VERSION 5.7 ;
BUSBITCHARS "[]" ;
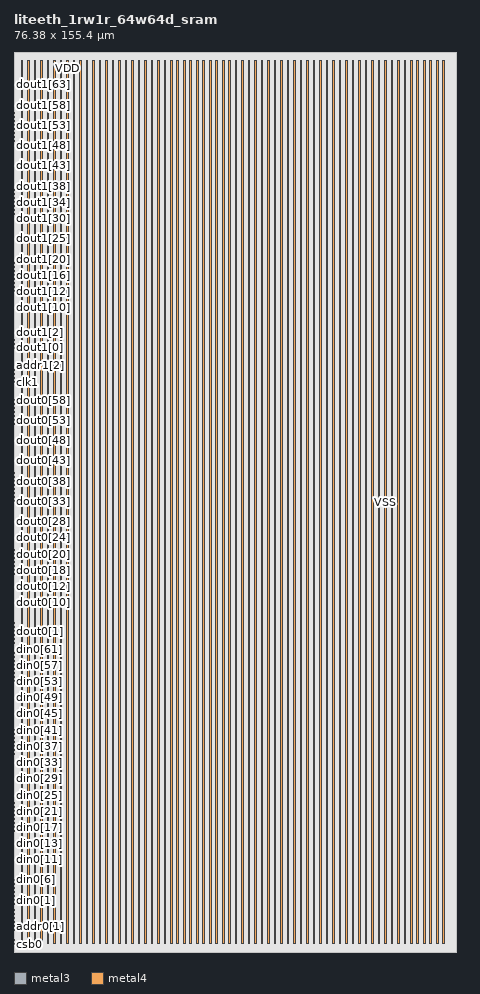
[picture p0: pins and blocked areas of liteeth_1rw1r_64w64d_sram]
MACRO liteeth_1rw1r_64w64d_sram
  FOREIGN liteeth_1rw1r_64w64d_sram 0 0 ;
  SYMMETRY X Y R90 ;
  SIZE 76.380 BY 155.400 ;
  CLASS BLOCK ;
  PIN clk0
    DIRECTION INPUT ;
    USE SIGNAL ;
    SHAPE ABUTMENT ;
    PORT
      LAYER metal3 ;
      RECT 0.000 1.365 0.070 1.435 ;
    END
  END clk0
  PIN csb0
    DIRECTION INPUT ;
    USE SIGNAL ;
    SHAPE ABUTMENT ;
    PORT
      LAYER metal3 ;
      RECT 0.000 2.065 0.070 2.135 ;
    END
  END csb0
  PIN web0
    DIRECTION INPUT ;
    USE SIGNAL ;
    SHAPE ABUTMENT ;
    PORT
      LAYER metal3 ;
      RECT 0.000 2.765 0.070 2.835 ;
    END
  END web0
  PIN addr0[0]
    DIRECTION INPUT ;
    USE SIGNAL ;
    SHAPE ABUTMENT ;
    PORT
      LAYER metal3 ;
      RECT 0.000 3.745 0.070 3.815 ;
    END
  END addr0[0]
  PIN addr0[1]
    DIRECTION INPUT ;
    USE SIGNAL ;
    SHAPE ABUTMENT ;
    PORT
      LAYER metal3 ;
      RECT 0.000 4.445 0.070 4.515 ;
    END
  END addr0[1]
  PIN addr0[2]
    DIRECTION INPUT ;
    USE SIGNAL ;
    SHAPE ABUTMENT ;
    PORT
      LAYER metal3 ;
      RECT 0.000 5.145 0.070 5.215 ;
    END
  END addr0[2]
  PIN addr0[3]
    DIRECTION INPUT ;
    USE SIGNAL ;
    SHAPE ABUTMENT ;
    PORT
      LAYER metal3 ;
      RECT 0.000 5.845 0.070 5.915 ;
    END
  END addr0[3]
  PIN addr0[4]
    DIRECTION INPUT ;
    USE SIGNAL ;
    SHAPE ABUTMENT ;
    PORT
      LAYER metal3 ;
      RECT 0.000 6.545 0.070 6.615 ;
    END
  END addr0[4]
  PIN addr0[5]
    DIRECTION INPUT ;
    USE SIGNAL ;
    SHAPE ABUTMENT ;
    PORT
      LAYER metal3 ;
      RECT 0.000 7.245 0.070 7.315 ;
    END
  END addr0[5]
  PIN din0[0]
    DIRECTION INPUT ;
    USE SIGNAL ;
    SHAPE ABUTMENT ;
    PORT
      LAYER metal3 ;
      RECT 0.000 8.225 0.070 8.295 ;
    END
  END din0[0]
  PIN din0[1]
    DIRECTION INPUT ;
    USE SIGNAL ;
    SHAPE ABUTMENT ;
    PORT
      LAYER metal3 ;
      RECT 0.000 8.925 0.070 8.995 ;
    END
  END din0[1]
  PIN din0[2]
    DIRECTION INPUT ;
    USE SIGNAL ;
    SHAPE ABUTMENT ;
    PORT
      LAYER metal3 ;
      RECT 0.000 9.625 0.070 9.695 ;
    END
  END din0[2]
  PIN din0[3]
    DIRECTION INPUT ;
    USE SIGNAL ;
    SHAPE ABUTMENT ;
    PORT
      LAYER metal3 ;
      RECT 0.000 10.325 0.070 10.395 ;
    END
  END din0[3]
  PIN din0[4]
    DIRECTION INPUT ;
    USE SIGNAL ;
    SHAPE ABUTMENT ;
    PORT
      LAYER metal3 ;
      RECT 0.000 11.025 0.070 11.095 ;
    END
  END din0[4]
  PIN din0[5]
    DIRECTION INPUT ;
    USE SIGNAL ;
    SHAPE ABUTMENT ;
    PORT
      LAYER metal3 ;
      RECT 0.000 11.725 0.070 11.795 ;
    END
  END din0[5]
  PIN din0[6]
    DIRECTION INPUT ;
    USE SIGNAL ;
    SHAPE ABUTMENT ;
    PORT
      LAYER metal3 ;
      RECT 0.000 12.425 0.070 12.495 ;
    END
  END din0[6]
  PIN din0[7]
    DIRECTION INPUT ;
    USE SIGNAL ;
    SHAPE ABUTMENT ;
    PORT
      LAYER metal3 ;
      RECT 0.000 13.125 0.070 13.195 ;
    END
  END din0[7]
  PIN din0[8]
    DIRECTION INPUT ;
    USE SIGNAL ;
    SHAPE ABUTMENT ;
    PORT
      LAYER metal3 ;
      RECT 0.000 13.825 0.070 13.895 ;
    END
  END din0[8]
  PIN din0[9]
    DIRECTION INPUT ;
    USE SIGNAL ;
    SHAPE ABUTMENT ;
    PORT
      LAYER metal3 ;
      RECT 0.000 14.525 0.070 14.595 ;
    END
  END din0[9]
  PIN din0[10]
    DIRECTION INPUT ;
    USE SIGNAL ;
    SHAPE ABUTMENT ;
    PORT
      LAYER metal3 ;
      RECT 0.000 15.225 0.070 15.295 ;
    END
  END din0[10]
  PIN din0[11]
    DIRECTION INPUT ;
    USE SIGNAL ;
    SHAPE ABUTMENT ;
    PORT
      LAYER metal3 ;
      RECT 0.000 15.925 0.070 15.995 ;
    END
  END din0[11]
  PIN din0[12]
    DIRECTION INPUT ;
    USE SIGNAL ;
    SHAPE ABUTMENT ;
    PORT
      LAYER metal3 ;
      RECT 0.000 16.625 0.070 16.695 ;
    END
  END din0[12]
  PIN din0[13]
    DIRECTION INPUT ;
    USE SIGNAL ;
    SHAPE ABUTMENT ;
    PORT
      LAYER metal3 ;
      RECT 0.000 17.325 0.070 17.395 ;
    END
  END din0[13]
  PIN din0[14]
    DIRECTION INPUT ;
    USE SIGNAL ;
    SHAPE ABUTMENT ;
    PORT
      LAYER metal3 ;
      RECT 0.000 18.025 0.070 18.095 ;
    END
  END din0[14]
  PIN din0[15]
    DIRECTION INPUT ;
    USE SIGNAL ;
    SHAPE ABUTMENT ;
    PORT
      LAYER metal3 ;
      RECT 0.000 18.725 0.070 18.795 ;
    END
  END din0[15]
  PIN din0[16]
    DIRECTION INPUT ;
    USE SIGNAL ;
    SHAPE ABUTMENT ;
    PORT
      LAYER metal3 ;
      RECT 0.000 19.425 0.070 19.495 ;
    END
  END din0[16]
  PIN din0[17]
    DIRECTION INPUT ;
    USE SIGNAL ;
    SHAPE ABUTMENT ;
    PORT
      LAYER metal3 ;
      RECT 0.000 20.125 0.070 20.195 ;
    END
  END din0[17]
  PIN din0[18]
    DIRECTION INPUT ;
    USE SIGNAL ;
    SHAPE ABUTMENT ;
    PORT
      LAYER metal3 ;
      RECT 0.000 20.825 0.070 20.895 ;
    END
  END din0[18]
  PIN din0[19]
    DIRECTION INPUT ;
    USE SIGNAL ;
    SHAPE ABUTMENT ;
    PORT
      LAYER metal3 ;
      RECT 0.000 21.525 0.070 21.595 ;
    END
  END din0[19]
  PIN din0[20]
    DIRECTION INPUT ;
    USE SIGNAL ;
    SHAPE ABUTMENT ;
    PORT
      LAYER metal3 ;
      RECT 0.000 22.225 0.070 22.295 ;
    END
  END din0[20]
  PIN din0[21]
    DIRECTION INPUT ;
    USE SIGNAL ;
    SHAPE ABUTMENT ;
    PORT
      LAYER metal3 ;
      RECT 0.000 22.925 0.070 22.995 ;
    END
  END din0[21]
  PIN din0[22]
    DIRECTION INPUT ;
    USE SIGNAL ;
    SHAPE ABUTMENT ;
    PORT
      LAYER metal3 ;
      RECT 0.000 23.625 0.070 23.695 ;
    END
  END din0[22]
  PIN din0[23]
    DIRECTION INPUT ;
    USE SIGNAL ;
    SHAPE ABUTMENT ;
    PORT
      LAYER metal3 ;
      RECT 0.000 24.325 0.070 24.395 ;
    END
  END din0[23]
  PIN din0[24]
    DIRECTION INPUT ;
    USE SIGNAL ;
    SHAPE ABUTMENT ;
    PORT
      LAYER metal3 ;
      RECT 0.000 25.025 0.070 25.095 ;
    END
  END din0[24]
  PIN din0[25]
    DIRECTION INPUT ;
    USE SIGNAL ;
    SHAPE ABUTMENT ;
    PORT
      LAYER metal3 ;
      RECT 0.000 25.725 0.070 25.795 ;
    END
  END din0[25]
  PIN din0[26]
    DIRECTION INPUT ;
    USE SIGNAL ;
    SHAPE ABUTMENT ;
    PORT
      LAYER metal3 ;
      RECT 0.000 26.425 0.070 26.495 ;
    END
  END din0[26]
  PIN din0[27]
    DIRECTION INPUT ;
    USE SIGNAL ;
    SHAPE ABUTMENT ;
    PORT
      LAYER metal3 ;
      RECT 0.000 27.125 0.070 27.195 ;
    END
  END din0[27]
  PIN din0[28]
    DIRECTION INPUT ;
    USE SIGNAL ;
    SHAPE ABUTMENT ;
    PORT
      LAYER metal3 ;
      RECT 0.000 27.825 0.070 27.895 ;
    END
  END din0[28]
  PIN din0[29]
    DIRECTION INPUT ;
    USE SIGNAL ;
    SHAPE ABUTMENT ;
    PORT
      LAYER metal3 ;
      RECT 0.000 28.525 0.070 28.595 ;
    END
  END din0[29]
  PIN din0[30]
    DIRECTION INPUT ;
    USE SIGNAL ;
    SHAPE ABUTMENT ;
    PORT
      LAYER metal3 ;
      RECT 0.000 29.225 0.070 29.295 ;
    END
  END din0[30]
  PIN din0[31]
    DIRECTION INPUT ;
    USE SIGNAL ;
    SHAPE ABUTMENT ;
    PORT
      LAYER metal3 ;
      RECT 0.000 29.925 0.070 29.995 ;
    END
  END din0[31]
  PIN din0[32]
    DIRECTION INPUT ;
    USE SIGNAL ;
    SHAPE ABUTMENT ;
    PORT
      LAYER metal3 ;
      RECT 0.000 30.625 0.070 30.695 ;
    END
  END din0[32]
  PIN din0[33]
    DIRECTION INPUT ;
    USE SIGNAL ;
    SHAPE ABUTMENT ;
    PORT
      LAYER metal3 ;
      RECT 0.000 31.325 0.070 31.395 ;
    END
  END din0[33]
  PIN din0[34]
    DIRECTION INPUT ;
    USE SIGNAL ;
    SHAPE ABUTMENT ;
    PORT
      LAYER metal3 ;
      RECT 0.000 32.025 0.070 32.095 ;
    END
  END din0[34]
  PIN din0[35]
    DIRECTION INPUT ;
    USE SIGNAL ;
    SHAPE ABUTMENT ;
    PORT
      LAYER metal3 ;
      RECT 0.000 32.725 0.070 32.795 ;
    END
  END din0[35]
  PIN din0[36]
    DIRECTION INPUT ;
    USE SIGNAL ;
    SHAPE ABUTMENT ;
    PORT
      LAYER metal3 ;
      RECT 0.000 33.425 0.070 33.495 ;
    END
  END din0[36]
  PIN din0[37]
    DIRECTION INPUT ;
    USE SIGNAL ;
    SHAPE ABUTMENT ;
    PORT
      LAYER metal3 ;
      RECT 0.000 34.125 0.070 34.195 ;
    END
  END din0[37]
  PIN din0[38]
    DIRECTION INPUT ;
    USE SIGNAL ;
    SHAPE ABUTMENT ;
    PORT
      LAYER metal3 ;
      RECT 0.000 34.825 0.070 34.895 ;
    END
  END din0[38]
  PIN din0[39]
    DIRECTION INPUT ;
    USE SIGNAL ;
    SHAPE ABUTMENT ;
    PORT
      LAYER metal3 ;
      RECT 0.000 35.525 0.070 35.595 ;
    END
  END din0[39]
  PIN din0[40]
    DIRECTION INPUT ;
    USE SIGNAL ;
    SHAPE ABUTMENT ;
    PORT
      LAYER metal3 ;
      RECT 0.000 36.225 0.070 36.295 ;
    END
  END din0[40]
  PIN din0[41]
    DIRECTION INPUT ;
    USE SIGNAL ;
    SHAPE ABUTMENT ;
    PORT
      LAYER metal3 ;
      RECT 0.000 36.925 0.070 36.995 ;
    END
  END din0[41]
  PIN din0[42]
    DIRECTION INPUT ;
    USE SIGNAL ;
    SHAPE ABUTMENT ;
    PORT
      LAYER metal3 ;
      RECT 0.000 37.625 0.070 37.695 ;
    END
  END din0[42]
  PIN din0[43]
    DIRECTION INPUT ;
    USE SIGNAL ;
    SHAPE ABUTMENT ;
    PORT
      LAYER metal3 ;
      RECT 0.000 38.325 0.070 38.395 ;
    END
  END din0[43]
  PIN din0[44]
    DIRECTION INPUT ;
    USE SIGNAL ;
    SHAPE ABUTMENT ;
    PORT
      LAYER metal3 ;
      RECT 0.000 39.025 0.070 39.095 ;
    END
  END din0[44]
  PIN din0[45]
    DIRECTION INPUT ;
    USE SIGNAL ;
    SHAPE ABUTMENT ;
    PORT
      LAYER metal3 ;
      RECT 0.000 39.725 0.070 39.795 ;
    END
  END din0[45]
  PIN din0[46]
    DIRECTION INPUT ;
    USE SIGNAL ;
    SHAPE ABUTMENT ;
    PORT
      LAYER metal3 ;
      RECT 0.000 40.425 0.070 40.495 ;
    END
  END din0[46]
  PIN din0[47]
    DIRECTION INPUT ;
    USE SIGNAL ;
    SHAPE ABUTMENT ;
    PORT
      LAYER metal3 ;
      RECT 0.000 41.125 0.070 41.195 ;
    END
  END din0[47]
  PIN din0[48]
    DIRECTION INPUT ;
    USE SIGNAL ;
    SHAPE ABUTMENT ;
    PORT
      LAYER metal3 ;
      RECT 0.000 41.825 0.070 41.895 ;
    END
  END din0[48]
  PIN din0[49]
    DIRECTION INPUT ;
    USE SIGNAL ;
    SHAPE ABUTMENT ;
    PORT
      LAYER metal3 ;
      RECT 0.000 42.525 0.070 42.595 ;
    END
  END din0[49]
  PIN din0[50]
    DIRECTION INPUT ;
    USE SIGNAL ;
    SHAPE ABUTMENT ;
    PORT
      LAYER metal3 ;
      RECT 0.000 43.225 0.070 43.295 ;
    END
  END din0[50]
  PIN din0[51]
    DIRECTION INPUT ;
    USE SIGNAL ;
    SHAPE ABUTMENT ;
    PORT
      LAYER metal3 ;
      RECT 0.000 43.925 0.070 43.995 ;
    END
  END din0[51]
  PIN din0[52]
    DIRECTION INPUT ;
    USE SIGNAL ;
    SHAPE ABUTMENT ;
    PORT
      LAYER metal3 ;
      RECT 0.000 44.625 0.070 44.695 ;
    END
  END din0[52]
  PIN din0[53]
    DIRECTION INPUT ;
    USE SIGNAL ;
    SHAPE ABUTMENT ;
    PORT
      LAYER metal3 ;
      RECT 0.000 45.325 0.070 45.395 ;
    END
  END din0[53]
  PIN din0[54]
    DIRECTION INPUT ;
    USE SIGNAL ;
    SHAPE ABUTMENT ;
    PORT
      LAYER metal3 ;
      RECT 0.000 46.025 0.070 46.095 ;
    END
  END din0[54]
  PIN din0[55]
    DIRECTION INPUT ;
    USE SIGNAL ;
    SHAPE ABUTMENT ;
    PORT
      LAYER metal3 ;
      RECT 0.000 46.725 0.070 46.795 ;
    END
  END din0[55]
  PIN din0[56]
    DIRECTION INPUT ;
    USE SIGNAL ;
    SHAPE ABUTMENT ;
    PORT
      LAYER metal3 ;
      RECT 0.000 47.425 0.070 47.495 ;
    END
  END din0[56]
  PIN din0[57]
    DIRECTION INPUT ;
    USE SIGNAL ;
    SHAPE ABUTMENT ;
    PORT
      LAYER metal3 ;
      RECT 0.000 48.125 0.070 48.195 ;
    END
  END din0[57]
  PIN din0[58]
    DIRECTION INPUT ;
    USE SIGNAL ;
    SHAPE ABUTMENT ;
    PORT
      LAYER metal3 ;
      RECT 0.000 48.825 0.070 48.895 ;
    END
  END din0[58]
  PIN din0[59]
    DIRECTION INPUT ;
    USE SIGNAL ;
    SHAPE ABUTMENT ;
    PORT
      LAYER metal3 ;
      RECT 0.000 49.525 0.070 49.595 ;
    END
  END din0[59]
  PIN din0[60]
    DIRECTION INPUT ;
    USE SIGNAL ;
    SHAPE ABUTMENT ;
    PORT
      LAYER metal3 ;
      RECT 0.000 50.225 0.070 50.295 ;
    END
  END din0[60]
  PIN din0[61]
    DIRECTION INPUT ;
    USE SIGNAL ;
    SHAPE ABUTMENT ;
    PORT
      LAYER metal3 ;
      RECT 0.000 50.925 0.070 50.995 ;
    END
  END din0[61]
  PIN din0[62]
    DIRECTION INPUT ;
    USE SIGNAL ;
    SHAPE ABUTMENT ;
    PORT
      LAYER metal3 ;
      RECT 0.000 51.625 0.070 51.695 ;
    END
  END din0[62]
  PIN din0[63]
    DIRECTION INPUT ;
    USE SIGNAL ;
    SHAPE ABUTMENT ;
    PORT
      LAYER metal3 ;
      RECT 0.000 52.325 0.070 52.395 ;
    END
  END din0[63]
  PIN dout0[0]
    DIRECTION OUTPUT ;
    USE SIGNAL ;
    SHAPE ABUTMENT ;
    PORT
      LAYER metal3 ;
      RECT 0.000 53.305 0.070 53.375 ;
    END
  END dout0[0]
  PIN dout0[1]
    DIRECTION OUTPUT ;
    USE SIGNAL ;
    SHAPE ABUTMENT ;
    PORT
      LAYER metal3 ;
      RECT 0.000 54.005 0.070 54.075 ;
    END
  END dout0[1]
  PIN dout0[2]
    DIRECTION OUTPUT ;
    USE SIGNAL ;
    SHAPE ABUTMENT ;
    PORT
      LAYER metal3 ;
      RECT 0.000 54.705 0.070 54.775 ;
    END
  END dout0[2]
  PIN dout0[3]
    DIRECTION OUTPUT ;
    USE SIGNAL ;
    SHAPE ABUTMENT ;
    PORT
      LAYER metal3 ;
      RECT 0.000 55.405 0.070 55.475 ;
    END
  END dout0[3]
  PIN dout0[4]
    DIRECTION OUTPUT ;
    USE SIGNAL ;
    SHAPE ABUTMENT ;
    PORT
      LAYER metal3 ;
      RECT 0.000 56.105 0.070 56.175 ;
    END
  END dout0[4]
  PIN dout0[5]
    DIRECTION OUTPUT ;
    USE SIGNAL ;
    SHAPE ABUTMENT ;
    PORT
      LAYER metal3 ;
      RECT 0.000 56.805 0.070 56.875 ;
    END
  END dout0[5]
  PIN dout0[6]
    DIRECTION OUTPUT ;
    USE SIGNAL ;
    SHAPE ABUTMENT ;
    PORT
      LAYER metal3 ;
      RECT 0.000 57.505 0.070 57.575 ;
    END
  END dout0[6]
  PIN dout0[7]
    DIRECTION OUTPUT ;
    USE SIGNAL ;
    SHAPE ABUTMENT ;
    PORT
      LAYER metal3 ;
      RECT 0.000 58.205 0.070 58.275 ;
    END
  END dout0[7]
  PIN dout0[8]
    DIRECTION OUTPUT ;
    USE SIGNAL ;
    SHAPE ABUTMENT ;
    PORT
      LAYER metal3 ;
      RECT 0.000 58.905 0.070 58.975 ;
    END
  END dout0[8]
  PIN dout0[9]
    DIRECTION OUTPUT ;
    USE SIGNAL ;
    SHAPE ABUTMENT ;
    PORT
      LAYER metal3 ;
      RECT 0.000 59.605 0.070 59.675 ;
    END
  END dout0[9]
  PIN dout0[10]
    DIRECTION OUTPUT ;
    USE SIGNAL ;
    SHAPE ABUTMENT ;
    PORT
      LAYER metal3 ;
      RECT 0.000 60.305 0.070 60.375 ;
    END
  END dout0[10]
  PIN dout0[11]
    DIRECTION OUTPUT ;
    USE SIGNAL ;
    SHAPE ABUTMENT ;
    PORT
      LAYER metal3 ;
      RECT 0.000 61.005 0.070 61.075 ;
    END
  END dout0[11]
  PIN dout0[12]
    DIRECTION OUTPUT ;
    USE SIGNAL ;
    SHAPE ABUTMENT ;
    PORT
      LAYER metal3 ;
      RECT 0.000 61.705 0.070 61.775 ;
    END
  END dout0[12]
  PIN dout0[13]
    DIRECTION OUTPUT ;
    USE SIGNAL ;
    SHAPE ABUTMENT ;
    PORT
      LAYER metal3 ;
      RECT 0.000 62.405 0.070 62.475 ;
    END
  END dout0[13]
  PIN dout0[14]
    DIRECTION OUTPUT ;
    USE SIGNAL ;
    SHAPE ABUTMENT ;
    PORT
      LAYER metal3 ;
      RECT 0.000 63.105 0.070 63.175 ;
    END
  END dout0[14]
  PIN dout0[15]
    DIRECTION OUTPUT ;
    USE SIGNAL ;
    SHAPE ABUTMENT ;
    PORT
      LAYER metal3 ;
      RECT 0.000 63.805 0.070 63.875 ;
    END
  END dout0[15]
  PIN dout0[16]
    DIRECTION OUTPUT ;
    USE SIGNAL ;
    SHAPE ABUTMENT ;
    PORT
      LAYER metal3 ;
      RECT 0.000 64.505 0.070 64.575 ;
    END
  END dout0[16]
  PIN dout0[17]
    DIRECTION OUTPUT ;
    USE SIGNAL ;
    SHAPE ABUTMENT ;
    PORT
      LAYER metal3 ;
      RECT 0.000 65.205 0.070 65.275 ;
    END
  END dout0[17]
  PIN dout0[18]
    DIRECTION OUTPUT ;
    USE SIGNAL ;
    SHAPE ABUTMENT ;
    PORT
      LAYER metal3 ;
      RECT 0.000 65.905 0.070 65.975 ;
    END
  END dout0[18]
  PIN dout0[19]
    DIRECTION OUTPUT ;
    USE SIGNAL ;
    SHAPE ABUTMENT ;
    PORT
      LAYER metal3 ;
      RECT 0.000 66.605 0.070 66.675 ;
    END
  END dout0[19]
  PIN dout0[20]
    DIRECTION OUTPUT ;
    USE SIGNAL ;
    SHAPE ABUTMENT ;
    PORT
      LAYER metal3 ;
      RECT 0.000 67.305 0.070 67.375 ;
    END
  END dout0[20]
  PIN dout0[21]
    DIRECTION OUTPUT ;
    USE SIGNAL ;
    SHAPE ABUTMENT ;
    PORT
      LAYER metal3 ;
      RECT 0.000 68.005 0.070 68.075 ;
    END
  END dout0[21]
  PIN dout0[22]
    DIRECTION OUTPUT ;
    USE SIGNAL ;
    SHAPE ABUTMENT ;
    PORT
      LAYER metal3 ;
      RECT 0.000 68.705 0.070 68.775 ;
    END
  END dout0[22]
  PIN dout0[23]
    DIRECTION OUTPUT ;
    USE SIGNAL ;
    SHAPE ABUTMENT ;
    PORT
      LAYER metal3 ;
      RECT 0.000 69.405 0.070 69.475 ;
    END
  END dout0[23]
  PIN dout0[24]
    DIRECTION OUTPUT ;
    USE SIGNAL ;
    SHAPE ABUTMENT ;
    PORT
      LAYER metal3 ;
      RECT 0.000 70.105 0.070 70.175 ;
    END
  END dout0[24]
  PIN dout0[25]
    DIRECTION OUTPUT ;
    USE SIGNAL ;
    SHAPE ABUTMENT ;
    PORT
      LAYER metal3 ;
      RECT 0.000 70.805 0.070 70.875 ;
    END
  END dout0[25]
  PIN dout0[26]
    DIRECTION OUTPUT ;
    USE SIGNAL ;
    SHAPE ABUTMENT ;
    PORT
      LAYER metal3 ;
      RECT 0.000 71.505 0.070 71.575 ;
    END
  END dout0[26]
  PIN dout0[27]
    DIRECTION OUTPUT ;
    USE SIGNAL ;
    SHAPE ABUTMENT ;
    PORT
      LAYER metal3 ;
      RECT 0.000 72.205 0.070 72.275 ;
    END
  END dout0[27]
  PIN dout0[28]
    DIRECTION OUTPUT ;
    USE SIGNAL ;
    SHAPE ABUTMENT ;
    PORT
      LAYER metal3 ;
      RECT 0.000 72.905 0.070 72.975 ;
    END
  END dout0[28]
  PIN dout0[29]
    DIRECTION OUTPUT ;
    USE SIGNAL ;
    SHAPE ABUTMENT ;
    PORT
      LAYER metal3 ;
      RECT 0.000 73.605 0.070 73.675 ;
    END
  END dout0[29]
  PIN dout0[30]
    DIRECTION OUTPUT ;
    USE SIGNAL ;
    SHAPE ABUTMENT ;
    PORT
      LAYER metal3 ;
      RECT 0.000 74.305 0.070 74.375 ;
    END
  END dout0[30]
  PIN dout0[31]
    DIRECTION OUTPUT ;
    USE SIGNAL ;
    SHAPE ABUTMENT ;
    PORT
      LAYER metal3 ;
      RECT 0.000 75.005 0.070 75.075 ;
    END
  END dout0[31]
  PIN dout0[32]
    DIRECTION OUTPUT ;
    USE SIGNAL ;
    SHAPE ABUTMENT ;
    PORT
      LAYER metal3 ;
      RECT 0.000 75.705 0.070 75.775 ;
    END
  END dout0[32]
  PIN dout0[33]
    DIRECTION OUTPUT ;
    USE SIGNAL ;
    SHAPE ABUTMENT ;
    PORT
      LAYER metal3 ;
      RECT 0.000 76.405 0.070 76.475 ;
    END
  END dout0[33]
  PIN dout0[34]
    DIRECTION OUTPUT ;
    USE SIGNAL ;
    SHAPE ABUTMENT ;
    PORT
      LAYER metal3 ;
      RECT 0.000 77.105 0.070 77.175 ;
    END
  END dout0[34]
  PIN dout0[35]
    DIRECTION OUTPUT ;
    USE SIGNAL ;
    SHAPE ABUTMENT ;
    PORT
      LAYER metal3 ;
      RECT 0.000 77.805 0.070 77.875 ;
    END
  END dout0[35]
  PIN dout0[36]
    DIRECTION OUTPUT ;
    USE SIGNAL ;
    SHAPE ABUTMENT ;
    PORT
      LAYER metal3 ;
      RECT 0.000 78.505 0.070 78.575 ;
    END
  END dout0[36]
  PIN dout0[37]
    DIRECTION OUTPUT ;
    USE SIGNAL ;
    SHAPE ABUTMENT ;
    PORT
      LAYER metal3 ;
      RECT 0.000 79.205 0.070 79.275 ;
    END
  END dout0[37]
  PIN dout0[38]
    DIRECTION OUTPUT ;
    USE SIGNAL ;
    SHAPE ABUTMENT ;
    PORT
      LAYER metal3 ;
      RECT 0.000 79.905 0.070 79.975 ;
    END
  END dout0[38]
  PIN dout0[39]
    DIRECTION OUTPUT ;
    USE SIGNAL ;
    SHAPE ABUTMENT ;
    PORT
      LAYER metal3 ;
      RECT 0.000 80.605 0.070 80.675 ;
    END
  END dout0[39]
  PIN dout0[40]
    DIRECTION OUTPUT ;
    USE SIGNAL ;
    SHAPE ABUTMENT ;
    PORT
      LAYER metal3 ;
      RECT 0.000 81.305 0.070 81.375 ;
    END
  END dout0[40]
  PIN dout0[41]
    DIRECTION OUTPUT ;
    USE SIGNAL ;
    SHAPE ABUTMENT ;
    PORT
      LAYER metal3 ;
      RECT 0.000 82.005 0.070 82.075 ;
    END
  END dout0[41]
  PIN dout0[42]
    DIRECTION OUTPUT ;
    USE SIGNAL ;
    SHAPE ABUTMENT ;
    PORT
      LAYER metal3 ;
      RECT 0.000 82.705 0.070 82.775 ;
    END
  END dout0[42]
  PIN dout0[43]
    DIRECTION OUTPUT ;
    USE SIGNAL ;
    SHAPE ABUTMENT ;
    PORT
      LAYER metal3 ;
      RECT 0.000 83.405 0.070 83.475 ;
    END
  END dout0[43]
  PIN dout0[44]
    DIRECTION OUTPUT ;
    USE SIGNAL ;
    SHAPE ABUTMENT ;
    PORT
      LAYER metal3 ;
      RECT 0.000 84.105 0.070 84.175 ;
    END
  END dout0[44]
  PIN dout0[45]
    DIRECTION OUTPUT ;
    USE SIGNAL ;
    SHAPE ABUTMENT ;
    PORT
      LAYER metal3 ;
      RECT 0.000 84.805 0.070 84.875 ;
    END
  END dout0[45]
  PIN dout0[46]
    DIRECTION OUTPUT ;
    USE SIGNAL ;
    SHAPE ABUTMENT ;
    PORT
      LAYER metal3 ;
      RECT 0.000 85.505 0.070 85.575 ;
    END
  END dout0[46]
  PIN dout0[47]
    DIRECTION OUTPUT ;
    USE SIGNAL ;
    SHAPE ABUTMENT ;
    PORT
      LAYER metal3 ;
      RECT 0.000 86.205 0.070 86.275 ;
    END
  END dout0[47]
  PIN dout0[48]
    DIRECTION OUTPUT ;
    USE SIGNAL ;
    SHAPE ABUTMENT ;
    PORT
      LAYER metal3 ;
      RECT 0.000 86.905 0.070 86.975 ;
    END
  END dout0[48]
  PIN dout0[49]
    DIRECTION OUTPUT ;
    USE SIGNAL ;
    SHAPE ABUTMENT ;
    PORT
      LAYER metal3 ;
      RECT 0.000 87.605 0.070 87.675 ;
    END
  END dout0[49]
  PIN dout0[50]
    DIRECTION OUTPUT ;
    USE SIGNAL ;
    SHAPE ABUTMENT ;
    PORT
      LAYER metal3 ;
      RECT 0.000 88.305 0.070 88.375 ;
    END
  END dout0[50]
  PIN dout0[51]
    DIRECTION OUTPUT ;
    USE SIGNAL ;
    SHAPE ABUTMENT ;
    PORT
      LAYER metal3 ;
      RECT 0.000 89.005 0.070 89.075 ;
    END
  END dout0[51]
  PIN dout0[52]
    DIRECTION OUTPUT ;
    USE SIGNAL ;
    SHAPE ABUTMENT ;
    PORT
      LAYER metal3 ;
      RECT 0.000 89.705 0.070 89.775 ;
    END
  END dout0[52]
  PIN dout0[53]
    DIRECTION OUTPUT ;
    USE SIGNAL ;
    SHAPE ABUTMENT ;
    PORT
      LAYER metal3 ;
      RECT 0.000 90.405 0.070 90.475 ;
    END
  END dout0[53]
  PIN dout0[54]
    DIRECTION OUTPUT ;
    USE SIGNAL ;
    SHAPE ABUTMENT ;
    PORT
      LAYER metal3 ;
      RECT 0.000 91.105 0.070 91.175 ;
    END
  END dout0[54]
  PIN dout0[55]
    DIRECTION OUTPUT ;
    USE SIGNAL ;
    SHAPE ABUTMENT ;
    PORT
      LAYER metal3 ;
      RECT 0.000 91.805 0.070 91.875 ;
    END
  END dout0[55]
  PIN dout0[56]
    DIRECTION OUTPUT ;
    USE SIGNAL ;
    SHAPE ABUTMENT ;
    PORT
      LAYER metal3 ;
      RECT 0.000 92.505 0.070 92.575 ;
    END
  END dout0[56]
  PIN dout0[57]
    DIRECTION OUTPUT ;
    USE SIGNAL ;
    SHAPE ABUTMENT ;
    PORT
      LAYER metal3 ;
      RECT 0.000 93.205 0.070 93.275 ;
    END
  END dout0[57]
  PIN dout0[58]
    DIRECTION OUTPUT ;
    USE SIGNAL ;
    SHAPE ABUTMENT ;
    PORT
      LAYER metal3 ;
      RECT 0.000 93.905 0.070 93.975 ;
    END
  END dout0[58]
  PIN dout0[59]
    DIRECTION OUTPUT ;
    USE SIGNAL ;
    SHAPE ABUTMENT ;
    PORT
      LAYER metal3 ;
      RECT 0.000 94.605 0.070 94.675 ;
    END
  END dout0[59]
  PIN dout0[60]
    DIRECTION OUTPUT ;
    USE SIGNAL ;
    SHAPE ABUTMENT ;
    PORT
      LAYER metal3 ;
      RECT 0.000 95.305 0.070 95.375 ;
    END
  END dout0[60]
  PIN dout0[61]
    DIRECTION OUTPUT ;
    USE SIGNAL ;
    SHAPE ABUTMENT ;
    PORT
      LAYER metal3 ;
      RECT 0.000 96.005 0.070 96.075 ;
    END
  END dout0[61]
  PIN dout0[62]
    DIRECTION OUTPUT ;
    USE SIGNAL ;
    SHAPE ABUTMENT ;
    PORT
      LAYER metal3 ;
      RECT 0.000 96.705 0.070 96.775 ;
    END
  END dout0[62]
  PIN dout0[63]
    DIRECTION OUTPUT ;
    USE SIGNAL ;
    SHAPE ABUTMENT ;
    PORT
      LAYER metal3 ;
      RECT 0.000 97.405 0.070 97.475 ;
    END
  END dout0[63]
  PIN clk1
    DIRECTION INPUT ;
    USE SIGNAL ;
    SHAPE ABUTMENT ;
    PORT
      LAYER metal3 ;
      RECT 0.000 98.385 0.070 98.455 ;
    END
  END clk1
  PIN csb1
    DIRECTION INPUT ;
    USE SIGNAL ;
    SHAPE ABUTMENT ;
    PORT
      LAYER metal3 ;
      RECT 0.000 99.085 0.070 99.155 ;
    END
  END csb1
  PIN addr1[0]
    DIRECTION INPUT ;
    USE SIGNAL ;
    SHAPE ABUTMENT ;
    PORT
      LAYER metal3 ;
      RECT 0.000 99.785 0.070 99.855 ;
    END
  END addr1[0]
  PIN addr1[1]
    DIRECTION INPUT ;
    USE SIGNAL ;
    SHAPE ABUTMENT ;
    PORT
      LAYER metal3 ;
      RECT 0.000 100.485 0.070 100.555 ;
    END
  END addr1[1]
  PIN addr1[2]
    DIRECTION INPUT ;
    USE SIGNAL ;
    SHAPE ABUTMENT ;
    PORT
      LAYER metal3 ;
      RECT 0.000 101.185 0.070 101.255 ;
    END
  END addr1[2]
  PIN addr1[3]
    DIRECTION INPUT ;
    USE SIGNAL ;
    SHAPE ABUTMENT ;
    PORT
      LAYER metal3 ;
      RECT 0.000 101.885 0.070 101.955 ;
    END
  END addr1[3]
  PIN addr1[4]
    DIRECTION INPUT ;
    USE SIGNAL ;
    SHAPE ABUTMENT ;
    PORT
      LAYER metal3 ;
      RECT 0.000 102.585 0.070 102.655 ;
    END
  END addr1[4]
  PIN addr1[5]
    DIRECTION INPUT ;
    USE SIGNAL ;
    SHAPE ABUTMENT ;
    PORT
      LAYER metal3 ;
      RECT 0.000 103.285 0.070 103.355 ;
    END
  END addr1[5]
  PIN dout1[0]
    DIRECTION OUTPUT ;
    USE SIGNAL ;
    SHAPE ABUTMENT ;
    PORT
      LAYER metal3 ;
      RECT 0.000 104.265 0.070 104.335 ;
    END
  END dout1[0]
  PIN dout1[1]
    DIRECTION OUTPUT ;
    USE SIGNAL ;
    SHAPE ABUTMENT ;
    PORT
      LAYER metal3 ;
      RECT 0.000 104.965 0.070 105.035 ;
    END
  END dout1[1]
  PIN dout1[2]
    DIRECTION OUTPUT ;
    USE SIGNAL ;
    SHAPE ABUTMENT ;
    PORT
      LAYER metal3 ;
      RECT 0.000 105.665 0.070 105.735 ;
    END
  END dout1[2]
  PIN dout1[3]
    DIRECTION OUTPUT ;
    USE SIGNAL ;
    SHAPE ABUTMENT ;
    PORT
      LAYER metal3 ;
      RECT 0.000 106.365 0.070 106.435 ;
    END
  END dout1[3]
  PIN dout1[4]
    DIRECTION OUTPUT ;
    USE SIGNAL ;
    SHAPE ABUTMENT ;
    PORT
      LAYER metal3 ;
      RECT 0.000 107.065 0.070 107.135 ;
    END
  END dout1[4]
  PIN dout1[5]
    DIRECTION OUTPUT ;
    USE SIGNAL ;
    SHAPE ABUTMENT ;
    PORT
      LAYER metal3 ;
      RECT 0.000 107.765 0.070 107.835 ;
    END
  END dout1[5]
  PIN dout1[6]
    DIRECTION OUTPUT ;
    USE SIGNAL ;
    SHAPE ABUTMENT ;
    PORT
      LAYER metal3 ;
      RECT 0.000 108.465 0.070 108.535 ;
    END
  END dout1[6]
  PIN dout1[7]
    DIRECTION OUTPUT ;
    USE SIGNAL ;
    SHAPE ABUTMENT ;
    PORT
      LAYER metal3 ;
      RECT 0.000 109.165 0.070 109.235 ;
    END
  END dout1[7]
  PIN dout1[8]
    DIRECTION OUTPUT ;
    USE SIGNAL ;
    SHAPE ABUTMENT ;
    PORT
      LAYER metal3 ;
      RECT 0.000 109.865 0.070 109.935 ;
    END
  END dout1[8]
  PIN dout1[9]
    DIRECTION OUTPUT ;
    USE SIGNAL ;
    SHAPE ABUTMENT ;
    PORT
      LAYER metal3 ;
      RECT 0.000 110.565 0.070 110.635 ;
    END
  END dout1[9]
  PIN dout1[10]
    DIRECTION OUTPUT ;
    USE SIGNAL ;
    SHAPE ABUTMENT ;
    PORT
      LAYER metal3 ;
      RECT 0.000 111.265 0.070 111.335 ;
    END
  END dout1[10]
  PIN dout1[11]
    DIRECTION OUTPUT ;
    USE SIGNAL ;
    SHAPE ABUTMENT ;
    PORT
      LAYER metal3 ;
      RECT 0.000 111.965 0.070 112.035 ;
    END
  END dout1[11]
  PIN dout1[12]
    DIRECTION OUTPUT ;
    USE SIGNAL ;
    SHAPE ABUTMENT ;
    PORT
      LAYER metal3 ;
      RECT 0.000 112.665 0.070 112.735 ;
    END
  END dout1[12]
  PIN dout1[13]
    DIRECTION OUTPUT ;
    USE SIGNAL ;
    SHAPE ABUTMENT ;
    PORT
      LAYER metal3 ;
      RECT 0.000 113.365 0.070 113.435 ;
    END
  END dout1[13]
  PIN dout1[14]
    DIRECTION OUTPUT ;
    USE SIGNAL ;
    SHAPE ABUTMENT ;
    PORT
      LAYER metal3 ;
      RECT 0.000 114.065 0.070 114.135 ;
    END
  END dout1[14]
  PIN dout1[15]
    DIRECTION OUTPUT ;
    USE SIGNAL ;
    SHAPE ABUTMENT ;
    PORT
      LAYER metal3 ;
      RECT 0.000 114.765 0.070 114.835 ;
    END
  END dout1[15]
  PIN dout1[16]
    DIRECTION OUTPUT ;
    USE SIGNAL ;
    SHAPE ABUTMENT ;
    PORT
      LAYER metal3 ;
      RECT 0.000 115.465 0.070 115.535 ;
    END
  END dout1[16]
  PIN dout1[17]
    DIRECTION OUTPUT ;
    USE SIGNAL ;
    SHAPE ABUTMENT ;
    PORT
      LAYER metal3 ;
      RECT 0.000 116.165 0.070 116.235 ;
    END
  END dout1[17]
  PIN dout1[18]
    DIRECTION OUTPUT ;
    USE SIGNAL ;
    SHAPE ABUTMENT ;
    PORT
      LAYER metal3 ;
      RECT 0.000 116.865 0.070 116.935 ;
    END
  END dout1[18]
  PIN dout1[19]
    DIRECTION OUTPUT ;
    USE SIGNAL ;
    SHAPE ABUTMENT ;
    PORT
      LAYER metal3 ;
      RECT 0.000 117.565 0.070 117.635 ;
    END
  END dout1[19]
  PIN dout1[20]
    DIRECTION OUTPUT ;
    USE SIGNAL ;
    SHAPE ABUTMENT ;
    PORT
      LAYER metal3 ;
      RECT 0.000 118.265 0.070 118.335 ;
    END
  END dout1[20]
  PIN dout1[21]
    DIRECTION OUTPUT ;
    USE SIGNAL ;
    SHAPE ABUTMENT ;
    PORT
      LAYER metal3 ;
      RECT 0.000 118.965 0.070 119.035 ;
    END
  END dout1[21]
  PIN dout1[22]
    DIRECTION OUTPUT ;
    USE SIGNAL ;
    SHAPE ABUTMENT ;
    PORT
      LAYER metal3 ;
      RECT 0.000 119.665 0.070 119.735 ;
    END
  END dout1[22]
  PIN dout1[23]
    DIRECTION OUTPUT ;
    USE SIGNAL ;
    SHAPE ABUTMENT ;
    PORT
      LAYER metal3 ;
      RECT 0.000 120.365 0.070 120.435 ;
    END
  END dout1[23]
  PIN dout1[24]
    DIRECTION OUTPUT ;
    USE SIGNAL ;
    SHAPE ABUTMENT ;
    PORT
      LAYER metal3 ;
      RECT 0.000 121.065 0.070 121.135 ;
    END
  END dout1[24]
  PIN dout1[25]
    DIRECTION OUTPUT ;
    USE SIGNAL ;
    SHAPE ABUTMENT ;
    PORT
      LAYER metal3 ;
      RECT 0.000 121.765 0.070 121.835 ;
    END
  END dout1[25]
  PIN dout1[26]
    DIRECTION OUTPUT ;
    USE SIGNAL ;
    SHAPE ABUTMENT ;
    PORT
      LAYER metal3 ;
      RECT 0.000 122.465 0.070 122.535 ;
    END
  END dout1[26]
  PIN dout1[27]
    DIRECTION OUTPUT ;
    USE SIGNAL ;
    SHAPE ABUTMENT ;
    PORT
      LAYER metal3 ;
      RECT 0.000 123.165 0.070 123.235 ;
    END
  END dout1[27]
  PIN dout1[28]
    DIRECTION OUTPUT ;
    USE SIGNAL ;
    SHAPE ABUTMENT ;
    PORT
      LAYER metal3 ;
      RECT 0.000 123.865 0.070 123.935 ;
    END
  END dout1[28]
  PIN dout1[29]
    DIRECTION OUTPUT ;
    USE SIGNAL ;
    SHAPE ABUTMENT ;
    PORT
      LAYER metal3 ;
      RECT 0.000 124.565 0.070 124.635 ;
    END
  END dout1[29]
  PIN dout1[30]
    DIRECTION OUTPUT ;
    USE SIGNAL ;
    SHAPE ABUTMENT ;
    PORT
      LAYER metal3 ;
      RECT 0.000 125.265 0.070 125.335 ;
    END
  END dout1[30]
  PIN dout1[31]
    DIRECTION OUTPUT ;
    USE SIGNAL ;
    SHAPE ABUTMENT ;
    PORT
      LAYER metal3 ;
      RECT 0.000 125.965 0.070 126.035 ;
    END
  END dout1[31]
  PIN dout1[32]
    DIRECTION OUTPUT ;
    USE SIGNAL ;
    SHAPE ABUTMENT ;
    PORT
      LAYER metal3 ;
      RECT 0.000 126.665 0.070 126.735 ;
    END
  END dout1[32]
  PIN dout1[33]
    DIRECTION OUTPUT ;
    USE SIGNAL ;
    SHAPE ABUTMENT ;
    PORT
      LAYER metal3 ;
      RECT 0.000 127.365 0.070 127.435 ;
    END
  END dout1[33]
  PIN dout1[34]
    DIRECTION OUTPUT ;
    USE SIGNAL ;
    SHAPE ABUTMENT ;
    PORT
      LAYER metal3 ;
      RECT 0.000 128.065 0.070 128.135 ;
    END
  END dout1[34]
  PIN dout1[35]
    DIRECTION OUTPUT ;
    USE SIGNAL ;
    SHAPE ABUTMENT ;
    PORT
      LAYER metal3 ;
      RECT 0.000 128.765 0.070 128.835 ;
    END
  END dout1[35]
  PIN dout1[36]
    DIRECTION OUTPUT ;
    USE SIGNAL ;
    SHAPE ABUTMENT ;
    PORT
      LAYER metal3 ;
      RECT 0.000 129.465 0.070 129.535 ;
    END
  END dout1[36]
  PIN dout1[37]
    DIRECTION OUTPUT ;
    USE SIGNAL ;
    SHAPE ABUTMENT ;
    PORT
      LAYER metal3 ;
      RECT 0.000 130.165 0.070 130.235 ;
    END
  END dout1[37]
  PIN dout1[38]
    DIRECTION OUTPUT ;
    USE SIGNAL ;
    SHAPE ABUTMENT ;
    PORT
      LAYER metal3 ;
      RECT 0.000 130.865 0.070 130.935 ;
    END
  END dout1[38]
  PIN dout1[39]
    DIRECTION OUTPUT ;
    USE SIGNAL ;
    SHAPE ABUTMENT ;
    PORT
      LAYER metal3 ;
      RECT 0.000 131.565 0.070 131.635 ;
    END
  END dout1[39]
  PIN dout1[40]
    DIRECTION OUTPUT ;
    USE SIGNAL ;
    SHAPE ABUTMENT ;
    PORT
      LAYER metal3 ;
      RECT 0.000 132.265 0.070 132.335 ;
    END
  END dout1[40]
  PIN dout1[41]
    DIRECTION OUTPUT ;
    USE SIGNAL ;
    SHAPE ABUTMENT ;
    PORT
      LAYER metal3 ;
      RECT 0.000 132.965 0.070 133.035 ;
    END
  END dout1[41]
  PIN dout1[42]
    DIRECTION OUTPUT ;
    USE SIGNAL ;
    SHAPE ABUTMENT ;
    PORT
      LAYER metal3 ;
      RECT 0.000 133.665 0.070 133.735 ;
    END
  END dout1[42]
  PIN dout1[43]
    DIRECTION OUTPUT ;
    USE SIGNAL ;
    SHAPE ABUTMENT ;
    PORT
      LAYER metal3 ;
      RECT 0.000 134.365 0.070 134.435 ;
    END
  END dout1[43]
  PIN dout1[44]
    DIRECTION OUTPUT ;
    USE SIGNAL ;
    SHAPE ABUTMENT ;
    PORT
      LAYER metal3 ;
      RECT 0.000 135.065 0.070 135.135 ;
    END
  END dout1[44]
  PIN dout1[45]
    DIRECTION OUTPUT ;
    USE SIGNAL ;
    SHAPE ABUTMENT ;
    PORT
      LAYER metal3 ;
      RECT 0.000 135.765 0.070 135.835 ;
    END
  END dout1[45]
  PIN dout1[46]
    DIRECTION OUTPUT ;
    USE SIGNAL ;
    SHAPE ABUTMENT ;
    PORT
      LAYER metal3 ;
      RECT 0.000 136.465 0.070 136.535 ;
    END
  END dout1[46]
  PIN dout1[47]
    DIRECTION OUTPUT ;
    USE SIGNAL ;
    SHAPE ABUTMENT ;
    PORT
      LAYER metal3 ;
      RECT 0.000 137.165 0.070 137.235 ;
    END
  END dout1[47]
  PIN dout1[48]
    DIRECTION OUTPUT ;
    USE SIGNAL ;
    SHAPE ABUTMENT ;
    PORT
      LAYER metal3 ;
      RECT 0.000 137.865 0.070 137.935 ;
    END
  END dout1[48]
  PIN dout1[49]
    DIRECTION OUTPUT ;
    USE SIGNAL ;
    SHAPE ABUTMENT ;
    PORT
      LAYER metal3 ;
      RECT 0.000 138.565 0.070 138.635 ;
    END
  END dout1[49]
  PIN dout1[50]
    DIRECTION OUTPUT ;
    USE SIGNAL ;
    SHAPE ABUTMENT ;
    PORT
      LAYER metal3 ;
      RECT 0.000 139.265 0.070 139.335 ;
    END
  END dout1[50]
  PIN dout1[51]
    DIRECTION OUTPUT ;
    USE SIGNAL ;
    SHAPE ABUTMENT ;
    PORT
      LAYER metal3 ;
      RECT 0.000 139.965 0.070 140.035 ;
    END
  END dout1[51]
  PIN dout1[52]
    DIRECTION OUTPUT ;
    USE SIGNAL ;
    SHAPE ABUTMENT ;
    PORT
      LAYER metal3 ;
      RECT 0.000 140.665 0.070 140.735 ;
    END
  END dout1[52]
  PIN dout1[53]
    DIRECTION OUTPUT ;
    USE SIGNAL ;
    SHAPE ABUTMENT ;
    PORT
      LAYER metal3 ;
      RECT 0.000 141.365 0.070 141.435 ;
    END
  END dout1[53]
  PIN dout1[54]
    DIRECTION OUTPUT ;
    USE SIGNAL ;
    SHAPE ABUTMENT ;
    PORT
      LAYER metal3 ;
      RECT 0.000 142.065 0.070 142.135 ;
    END
  END dout1[54]
  PIN dout1[55]
    DIRECTION OUTPUT ;
    USE SIGNAL ;
    SHAPE ABUTMENT ;
    PORT
      LAYER metal3 ;
      RECT 0.000 142.765 0.070 142.835 ;
    END
  END dout1[55]
  PIN dout1[56]
    DIRECTION OUTPUT ;
    USE SIGNAL ;
    SHAPE ABUTMENT ;
    PORT
      LAYER metal3 ;
      RECT 0.000 143.465 0.070 143.535 ;
    END
  END dout1[56]
  PIN dout1[57]
    DIRECTION OUTPUT ;
    USE SIGNAL ;
    SHAPE ABUTMENT ;
    PORT
      LAYER metal3 ;
      RECT 0.000 144.165 0.070 144.235 ;
    END
  END dout1[57]
  PIN dout1[58]
    DIRECTION OUTPUT ;
    USE SIGNAL ;
    SHAPE ABUTMENT ;
    PORT
      LAYER metal3 ;
      RECT 0.000 144.865 0.070 144.935 ;
    END
  END dout1[58]
  PIN dout1[59]
    DIRECTION OUTPUT ;
    USE SIGNAL ;
    SHAPE ABUTMENT ;
    PORT
      LAYER metal3 ;
      RECT 0.000 145.565 0.070 145.635 ;
    END
  END dout1[59]
  PIN dout1[60]
    DIRECTION OUTPUT ;
    USE SIGNAL ;
    SHAPE ABUTMENT ;
    PORT
      LAYER metal3 ;
      RECT 0.000 146.265 0.070 146.335 ;
    END
  END dout1[60]
  PIN dout1[61]
    DIRECTION OUTPUT ;
    USE SIGNAL ;
    SHAPE ABUTMENT ;
    PORT
      LAYER metal3 ;
      RECT 0.000 146.965 0.070 147.035 ;
    END
  END dout1[61]
  PIN dout1[62]
    DIRECTION OUTPUT ;
    USE SIGNAL ;
    SHAPE ABUTMENT ;
    PORT
      LAYER metal3 ;
      RECT 0.000 147.665 0.070 147.735 ;
    END
  END dout1[62]
  PIN dout1[63]
    DIRECTION OUTPUT ;
    USE SIGNAL ;
    SHAPE ABUTMENT ;
    PORT
      LAYER metal3 ;
      RECT 0.000 148.365 0.070 148.435 ;
    END
  END dout1[63]
  PIN VSS
    DIRECTION INOUT ;
    USE GROUND ;
    PORT
      LAYER metal4 ;
      RECT 1.260 1.400 1.540 154.000 ;
      RECT 3.500 1.400 3.780 154.000 ;
      RECT 5.740 1.400 6.020 154.000 ;
      RECT 7.980 1.400 8.260 154.000 ;
      RECT 10.220 1.400 10.500 154.000 ;
      RECT 12.460 1.400 12.740 154.000 ;
      RECT 14.700 1.400 14.980 154.000 ;
      RECT 16.940 1.400 17.220 154.000 ;
      RECT 19.180 1.400 19.460 154.000 ;
      RECT 21.420 1.400 21.700 154.000 ;
      RECT 23.660 1.400 23.940 154.000 ;
      RECT 25.900 1.400 26.180 154.000 ;
      RECT 28.140 1.400 28.420 154.000 ;
      RECT 30.380 1.400 30.660 154.000 ;
      RECT 32.620 1.400 32.900 154.000 ;
      RECT 34.860 1.400 35.140 154.000 ;
      RECT 37.100 1.400 37.380 154.000 ;
      RECT 39.340 1.400 39.620 154.000 ;
      RECT 41.580 1.400 41.860 154.000 ;
      RECT 43.820 1.400 44.100 154.000 ;
      RECT 46.060 1.400 46.340 154.000 ;
      RECT 48.300 1.400 48.580 154.000 ;
      RECT 50.540 1.400 50.820 154.000 ;
      RECT 52.780 1.400 53.060 154.000 ;
      RECT 55.020 1.400 55.300 154.000 ;
      RECT 57.260 1.400 57.540 154.000 ;
      RECT 59.500 1.400 59.780 154.000 ;
      RECT 61.740 1.400 62.020 154.000 ;
      RECT 63.980 1.400 64.260 154.000 ;
      RECT 66.220 1.400 66.500 154.000 ;
      RECT 68.460 1.400 68.740 154.000 ;
      RECT 70.700 1.400 70.980 154.000 ;
      RECT 72.940 1.400 73.220 154.000 ;
    END
  END VSS
  PIN VDD
    DIRECTION INOUT ;
    USE POWER ;
    PORT
      LAYER metal4 ;
      RECT 2.380 1.400 2.660 154.000 ;
      RECT 4.620 1.400 4.900 154.000 ;
      RECT 6.860 1.400 7.140 154.000 ;
      RECT 9.100 1.400 9.380 154.000 ;
      RECT 11.340 1.400 11.620 154.000 ;
      RECT 13.580 1.400 13.860 154.000 ;
      RECT 15.820 1.400 16.100 154.000 ;
      RECT 18.060 1.400 18.340 154.000 ;
      RECT 20.300 1.400 20.580 154.000 ;
      RECT 22.540 1.400 22.820 154.000 ;
      RECT 24.780 1.400 25.060 154.000 ;
      RECT 27.020 1.400 27.300 154.000 ;
      RECT 29.260 1.400 29.540 154.000 ;
      RECT 31.500 1.400 31.780 154.000 ;
      RECT 33.740 1.400 34.020 154.000 ;
      RECT 35.980 1.400 36.260 154.000 ;
      RECT 38.220 1.400 38.500 154.000 ;
      RECT 40.460 1.400 40.740 154.000 ;
      RECT 42.700 1.400 42.980 154.000 ;
      RECT 44.940 1.400 45.220 154.000 ;
      RECT 47.180 1.400 47.460 154.000 ;
      RECT 49.420 1.400 49.700 154.000 ;
      RECT 51.660 1.400 51.940 154.000 ;
      RECT 53.900 1.400 54.180 154.000 ;
      RECT 56.140 1.400 56.420 154.000 ;
      RECT 58.380 1.400 58.660 154.000 ;
      RECT 60.620 1.400 60.900 154.000 ;
      RECT 62.860 1.400 63.140 154.000 ;
      RECT 65.100 1.400 65.380 154.000 ;
      RECT 67.340 1.400 67.620 154.000 ;
      RECT 69.580 1.400 69.860 154.000 ;
      RECT 71.820 1.400 72.100 154.000 ;
      RECT 74.060 1.400 74.340 154.000 ;
    END
  END VDD
  OBS
    LAYER metal1 ;
    RECT 0 0 76.380 155.400 ;
    LAYER metal2 ;
    RECT 0 0 76.380 155.400 ;
    LAYER metal3 ;
    RECT 0.070 0 76.380 155.400 ;
    LAYER metal4 ;
    RECT 0 0 76.380 155.400 ;
    LAYER OVERLAP ;
    RECT 0 0 76.380 155.400 ;
  END
END liteeth_1rw1r_64w64d_sram

END LIBRARY
